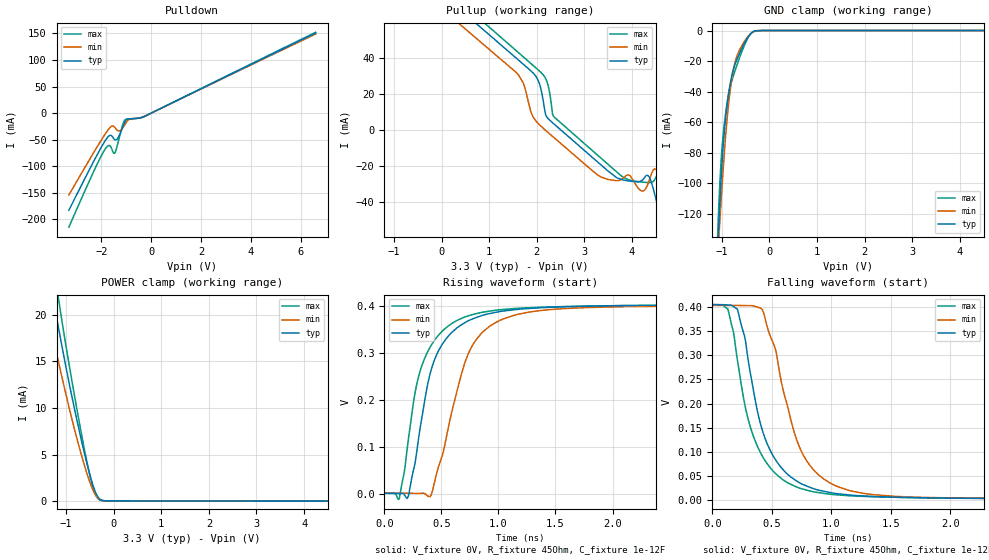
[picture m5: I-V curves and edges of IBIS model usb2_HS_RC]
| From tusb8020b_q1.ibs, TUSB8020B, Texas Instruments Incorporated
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|   USB 2.0 High Speed mode, for DP pin 240MHz (Internal Termination ON) with
|   recommended C load of 1pF.
[Model]   usb2_HS_RC
Model_type   I/O
Polarity   Non-Inverting
Enable   Active-High
Vmeas = 202mV
Vref = 0
Rref = 45
Cref =1pF
Vinl = 150mV
Vinh = 360mV
|   typ   min   max
|EXCEPTION   (nom PVT)   (Slow PVT) (Fast PVT)
C_comp   5.8941pF   5.4228pF   6.1646pF
[Voltage Range]   3.3   2.97   3.465
[Temperature Range]   27   105   -40
[Pullup Reference]   3.3   2.97   3.465
[Pulldown Reference]   0   0   0
[Power Clamp Reference]   3.3   2.97   3.465
[GND Clamp Reference]   0   0   0
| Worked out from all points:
|   slope of the pulldown table from 0 to 0.495 V, typ, clamps not added: 43.6 ohm
|   slope of the pullup table from 0 to 0.495 V, typ, clamps not added: 43.8 ohm
|   GND clamp passes 1 mA (typ) near -0.35 V on its own axis
|   POWER clamp passes 1 mA (typ) near -0.38 V on its own axis
|   falling waveform, V_fixture 0V, R_fixture 45Ohm, C_fixture 1e-12F: 20-80 % time 252ps typ, 275ps min, 250ps max; typ from 0.405 V to 0.002 V
|   rising waveform, V_fixture 0V, R_fixture 45Ohm, C_fixture 1e-12F: 20-80 % time 240ps typ, 278ps min, 235ps max; typ from 0.002 V to 0.404 V
[Pulldown]
|   Voltage   I(typ)   I(min)   I(max)
-3.3V     -182.7mA   -154mA     -214.5mA
-2.109V   -73.47mA   -59.12mA   -90.55mA
-1.836V   -51.34mA   -38.81mA   -67.06mA
-1.687V   -42.74mA   -29.04mA   -60.76mA
-1.588V   -42.26mA   -24.56mA   -66.11mA
-1.464V   -49.94mA   -26.46mA   -75.27mA
-1.265V   -40.67mA   -33.14mA   -44.1mA
-1.141V   -26.63mA   -28.06mA   -22.45mA
-1.042V   -16mA      -21.02mA   -12.18mA
-868.4mV  -10.68mA   -11.28mA   -10.85mA
-297.7mV  -6.74mA    -6.624mA   -6.826mA
6.6V      150.7mA    148.8mA    152.1mA
[GND Clamp]
|   Voltage   I(typ)   I(min)   I(max)
-3.3V     -3.521A    -2.996A    -4.111A
-1.092V   -145.9mA   -151.2mA   -136.4mA
-1.067V   -128.4mA   -137.7mA   -116.4mA
-1.042V   -112.2mA   -124.7mA   -99.36mA
-1.017V   -97.56mA   -112.1mA   -85.68mA
-967.7mV  -73.5mA    -88.57mA   -66.63mA
-893.2mV  -49.51mA   -59.02mA   -47.86mA
-818.8mV  -33.69mA   -37.74mA   -35.76mA
-669.9mV  -17.99mA   -15.57mA   -21.42mA
-471.4mV  -5.326mA   -4.698mA   -5.944mA
-322.6mV  -523.8uA   -615.4uA   -432uA
6.6V      0A         0A         0A
[Pullup]
|   Voltage   I(typ)   I(min)   I(max)
-3.3V     150.7mA    141.5mA    155.9mA
1.563V    39.81mA    31.86mA    43.93mA
1.96V     30.34mA    5.602mA    34.77mA
2.208V    7.102mA    -875.8uA   27.06mA
2.357V    3.277mA    -4.287mA   7.257mA
3.275V    -17.82mA   -24.99mA   -14.06mA
4.342V    -25.52mA   -29.54mA   -29.28mA
4.565V    -44.49mA   -24.78mA   -25.96mA
4.764V    -50.65mA   -42.33mA   -56.23mA
4.913V    -44.86mA   -57.23mA   -80.87mA
5.086V    -57mA      -75.14mA   -71.32mA
6.6V      -238.4mA   -237.7mA   -255.4mA
[POWER Clamp]
|   Voltage   I(typ)   I(min)   I(max)
-3.3V     96.76mA    79.79mA    115.2mA
-1.538V   29.26mA    23.71mA    34.64mA
-1.365V   24.34mA    19.65mA    28.67mA
-1.315V   22.95mA    18.5mA     26.98mA
-1.216V   20.19mA    16.23mA    23.63mA
-1.141V   18.14mA    14.55mA    21.16mA
-843.6mV  10.42mA    8.146mA    11.95mA
-570.7mV  4.224mA    3.128mA    4.449mA
-421.8mV  1.503mA    1.054mA    1.277mA
-372.2mV  844uA      587uA      607.5uA
-297.7mV  244.6uA    181.6uA    136.8uA
6.6V      0A         0A         0A
[Ramp]
R_load = 45
|   typ   min   max
dV/dt_r   0.241364/2.40298e-10   0.240102/2.77902e-10   0.241582/2.34784e-10
dV/dt_f   0.24137/2.52037e-10   0.240087/2.75243e-10   0.241515/2.50484e-10
[Falling Waveform]
V_fixture = 0V
V_fixture_min = 0V
V_fixture_max = 0V
R_fixture = 45Ohm
C_fixture = 1e-12F
|   Time   V(typ)   V(min)   V(max)
0s        404.5mV    402.7mV    404.6mV
130ps     403.7mV    402.8mV    395.2mV
210ps     394.8mV    402.7mV    290.8mV
300ps     291.2mV    402.3mV    168.3mV
420ps     144.6mV    393.5mV    91.43mV
530ps     84.09mV    312.2mV    55.57mV
680ps     44.73mV    147.1mV    30.66mV
860ps     23.36mV    60.43mV    17.27mV
1.18ns    10.47mV    18.61mV    9.102mV
3.5ns     2.259mV    2.567mV    2.121mV
[Rising Waveform]
V_fixture = 0V
V_fixture_min = 0V
V_fixture_max = 0V
R_fixture = 45Ohm
C_fixture = 1e-12F
|   Time   V(typ)   V(min)   V(max)
0s        1.753mV    1.976mV    1.462mV
130ps     1.073mV    1.846mV    -10.27mV
210ps     -4.468mV   1.677mV    116.9mV
290ps     102.3mV    1.34mV     241.2mV
400ps     256.1mV    -5.588mV   312.8mV
500ps     316.5mV    76.65mV    345.6mV
640ps     355mV      223.1mV    370.5mV
810ps     376.8mV    331mV      384.9mV
1.14ns    393mV      381.4mV    395.5mV
3.5ns     404mV      402.1mV    404.1mV
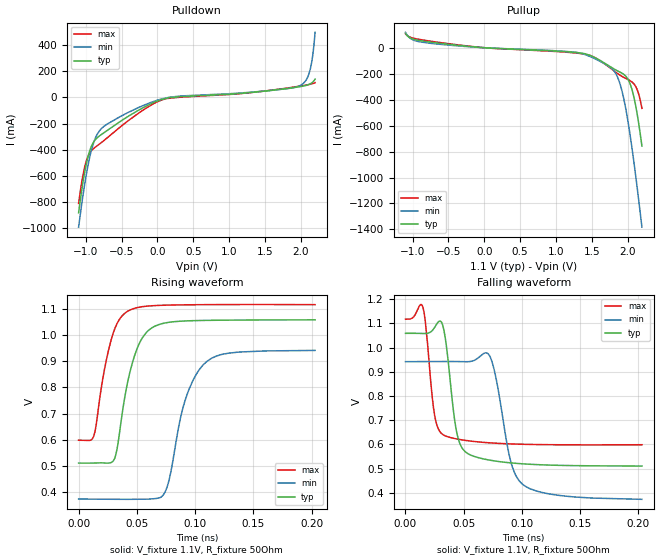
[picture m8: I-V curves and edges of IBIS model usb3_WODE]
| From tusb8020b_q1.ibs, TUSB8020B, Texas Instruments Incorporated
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|   USB 3.0 No De-Emphasis mode, for SSTXP/N pin  2.5GHz
[Model]   usb3_WODE
Model_type   Output
Polarity   Non-Inverting
Vmeas = 0.75
Vref = 1.1
Rref = 50
|   typ   min   max
|   (nom PVT)   (Fast PVT)   (slow PVT)
C_comp   0.5286pF   0.5195pF   0.5464pF
[Voltage Range]   1.1   0.99   1.155
[Temperature Range]   27   105   -40
[Pullup Reference]   1.1   0.99   1.155
[Pulldown Reference]   0   0   0
[Power Clamp Reference]   1.1   0.99   1.155
[GND Clamp Reference]   0   0   0
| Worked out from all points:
|   slope of the pulldown table from 0 to 0.165 V, typ, clamps not added: 6.7 ohm
|   slope of the pullup table from 0 to 0.165 V, typ, clamps not added: 31.1 ohm
|   falling waveform, V_fixture 1.1V, R_fixture 50Ohm: 20-80 % time 8.99ps typ, 13.8ps min, 6.77ps max; typ from 1.06 V to 0.51 V
|   rising waveform, V_fixture 1.1V, R_fixture 50Ohm: 20-80 % time 15.3ps typ, 18.7ps min, 13.6ps max; typ from 0.51 V to 1.06 V
[Pulldown]
|   Voltage   I(typ)   I(min)   I(max)
-1.1V     -882.4mA   -992.9mA   -811.1mA
-1.017V   -579.6mA   -673.2mA   -537.6mA
-942.9mV  -405.4mA   -453.1mA   -424mA
-851.9mV  -314.6mA   -294.1mA   -374.2mA
-752.6mV  -272.7mA   -224.2mA   -332.7mA
-272.9mV  -100.7mA   -79.78mA   -124.3mA
74.44mV   -13.02mA   -9.468mA   -16.58mA
1.985V    82.05mA    89.01mA    86.68mA
2.068V    90.95mA    126.5mA    93.9mA
2.126V    102mA      201mA      100.1mA
2.167V    117.1mA    320mA      106.1mA
2.2V      139.9mA    498.5mA    113mA
[Pullup]
|   Voltage   I(typ)   I(min)   I(max)
-1.1V     113.7mA    121.3mA    110.2mA
-992.5mV  68.76mA    62.34mA    76.36mA
-760.9mV  45.98mA    37.07mA    53.88mA
24.81mV   1.446mA    1.636mA    1.318mA
1.406V    -44.63mA   -50.53mA   -47.08mA
1.77V     -147.9mA   -154mA     -159.6mA
1.877V    -181.7mA   -249.3mA   -203.5mA
1.968V    -213.9mA   -450.7mA   -232.4mA
2.026V    -265.2mA   -640.2mA   -249.1mA
2.084V    -370mA     -865.4mA   -274.6mA
2.142V    -537.7mA   -1.116A    -333.8mA
2.2V      -757mA     -1.383A    -465.6mA
[Ramp]
R_load = 50
|   typ   min   max
dV/dt_r   0.328876/1.53144e-11   0.341033/1.87105e-11   0.311149/1.36392e-11
dV/dt_f   0.328891/8.99406e-12   0.341098/1.37718e-11   0.311003/6.76744e-12
[Falling Waveform]
V_fixture = 1.1V
V_fixture_min = 0.99V
V_fixture_max = 1.155V
R_fixture = 50Ohm
C_fixture = 0F
|   Time   V(typ)   V(min)   V(max)
0s        1.059V     941.6mV    1.117V
15ps      1.058V     941.9mV    1.167V
25ps      1.083V     942.1mV    720.9mV
33ps      1.072V     942.2mV    638mV
44ps      649.6mV    942mV      622.4mV
53ps      563.5mV    941.4mV    615.4mV
73ps      534.3mV    958mV      606.2mV
90ps      523.8mV    536.5mV    602mV
101ps     519.6mV    433.3mV    600.4mV
203ps     510.4mV    373.1mV    598.5mV
[Rising Waveform]
V_fixture = 1.1V
V_fixture_min = 0.99V
V_fixture_max = 1.155V
R_fixture = 50Ohm
C_fixture = 0F
|   Time   V(typ)   V(min)   V(max)
0s        510.5mV    373.3mV    598.1mV
13ps      510.7mV    372.6mV    613.6mV
22ps      510.9mV    372.3mV    863.8mV
30ps      520.3mV    372mV      1.012V
42ps      817.9mV    371.8mV    1.091V
55ps      991.7mV    372.3mV    1.109V
74ps      1.046V     398.1mV    1.115V
92ps      1.054V     758.2mV    1.116V
110ps     1.057V     898.9mV    1.117V
203ps     1.059V     941.6mV    1.117V
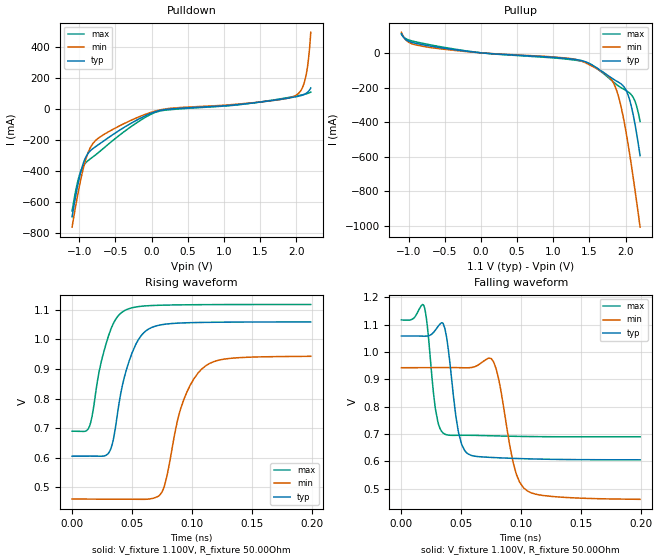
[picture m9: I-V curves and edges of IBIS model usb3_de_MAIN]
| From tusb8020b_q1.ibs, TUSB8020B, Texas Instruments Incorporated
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|USB 3.0 De-Emphasis MAIN Buffer, for SSTXP/SSTXN pins 2.5GHz(1.25GHz to see De-Emphasis)
[Model]   usb3_de_MAIN
Model_type   Output
Vmeas = 0.8
Vref = 1.1
Rref = 50
C_comp   0.5286pF   0.5195pF   0.5464pF
[Voltage Range]   1.1   0.99   1.155
[Temperature Range]   27   105   -40
[Pullup Reference]   1.1   0.99   1.155
[Pulldown Reference]   -0   -0   -0
[Power Clamp Reference]   1.1   0.99   1.155
[GND Clamp Reference]   -0   -0   -0
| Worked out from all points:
|   slope of the pulldown table from 0 to 0.165 V, typ, clamps not added: 7.83 ohm
|   slope of the pullup table from 0 to 0.165 V, typ, clamps not added: 30.4 ohm
|   falling waveform, V_fixture 1.100V, R_fixture 50.00Ohm: 20-80 % time 7.94ps typ, 12.1ps min, 6.06ps max; typ from 1.06 V to 0.605 V
|   rising waveform, V_fixture 1.100V, R_fixture 50.00Ohm: 20-80 % time 15.6ps typ, 18.7ps min, 14.1ps max; typ from 0.605 V to 1.06 V
[Pulldown]
|   Voltage   I(typ)   I(min)   I(max)
-1.1V     -696.3mA   -762.7mA   -658.5mA
-1.017V   -482.8mA   -542.2mA   -459.3mA
-942.9mV  -348.4mA   -380.8mA   -366.2mA
-860.2mV  -276.3mA   -262mA     -326.5mA
-760.9mV  -239mA     -197.7mA   -291.2mA
-256.4mV  -85.42mA   -67.68mA   -105.3mA
99.25mV   -11.89mA   -8.313mA   -15.58mA
1.977V    76.75mA    82.46mA    81.25mA
2.059V    85.22mA    115.8mA    88.44mA
2.117V    95.32mA    181mA      94.39mA
2.167V    112.5mA    315.4mA    101.4mA
2.2V      135.3mA    493.8mA    108.3mA
[Pullup]
|   Voltage   I(typ)   I(min)   I(max)
-1.1V     113.7mA    121.3mA    110.2mA
-1.001V   70.28mA    64.42mA    77.6mA
-769.2mV  46.62mA    37.62mA    54.61mA
0V        2.426mA    2.416mA    2.485mA
1.398V    -42.93mA   -46.86mA   -46.14mA
1.753V    -128.1mA   -131.2mA   -138.3mA
1.861V    -157.9mA   -198.3mA   -176.3mA
1.96V     -186mA     -354.6mA   -204.7mA
2.026V    -233.3mA   -507.1mA   -221.1mA
2.076V    -302.3mA   -638.6mA   -239mA
2.142V    -440.6mA   -829.4mA   -293mA
2.2V      -593.4mA   -1.007A    -395.5mA
[Ramp]
R_load = 50.00Ohm
|   typ   min   max
dV/dt_r   271.949mV/15.625ps  289.075mV/18.671ps  256.692mV/14.067ps
dV/dt_f   271.945mV/7.956ps   289.075mV/12.138ps  256.673mV/6.060ps
[Falling Waveform]
V_fixture = 1.100V
V_fixture_min = 990.000mV
V_fixture_max = 1.155V
R_fixture = 50.00Ohm
|   Time   V(typ)   V(min)   V(max)
0s        1.059V     942.5mV    1.117V
18.63ps   1.058V     942.8mV    1.171V
28.48ps   1.081V     943mV      789.9mV
36.18ps   1.088V     943.1mV    699.5mV
47.67ps   705.5mV    942.9mV    695.2mV
55.58ps   627.3mV    942.3mV    695.3mV
77.14ps   613.7mV    962.7mV    693.2mV
93.35ps   610.7mV    594.9mV    691.6mV
105.3ps   609.1mV    491.1mV    690.8mV
199.4ps   605.5mV    460.7mV    689.6mV
[Rising Waveform]
V_fixture = 1.100V
V_fixture_min = 990.000mV
V_fixture_max = 1.155V
R_fixture = 50.00Ohm
|   Time   V(typ)   V(min)   V(max)
0s        605.4mV    460.7mV    689.7mV
14.55ps   605.4mV    460.3mV    706.2mV
22.72ps   605.2mV    460.1mV    893.4mV
31.07ps   619.1mV    460mV      1.019V
43.89ps   875.7mV    459.9mV    1.097V
58.21ps   1.015V     459.5mV    1.112V
75.08ps   1.049V     483.8mV    1.115V
93.35ps   1.055V     797mV      1.116V
112ps     1.057V     911.5mV    1.117V
199.4ps   1.059V     942.5mV    1.117V
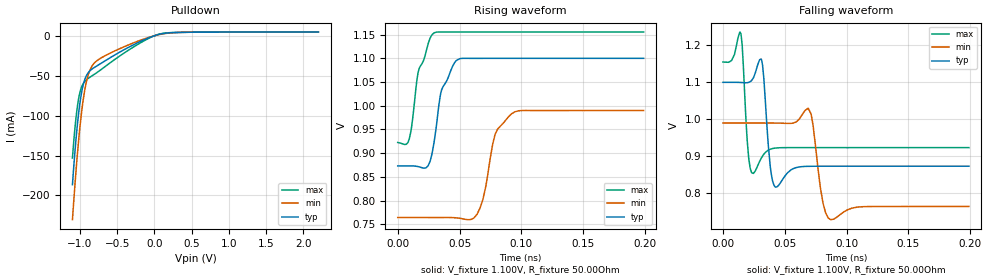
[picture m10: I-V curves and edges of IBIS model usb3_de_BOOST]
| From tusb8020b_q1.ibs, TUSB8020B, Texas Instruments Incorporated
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|USB 3.0 De-Emphasis BOOST Buffer, for SSTXP/SSTXN pins 2.5GHz(1.25GHz to see De-Emphasis)
[Model]   usb3_de_BOOST
Model_type   Open_drain
Vmeas = 1.1
Vref = 1.1
Rref = 50
|   typ   min   max
C_comp   0 0 0
[Voltage Range]   1.1   0.99   1.155
[Temperature Range]   27   105   -40
[Pullup Reference]   1.1   0.99   1.155
[Pulldown Reference]   -0   -0   -0
[Power Clamp Reference]   1.1   0.99   1.155
[GND Clamp Reference]   -0   -0   -0
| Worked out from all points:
|   slope of the pulldown table from 0 to 0.165 V, typ, clamps not added: 49.2 ohm
|   falling waveform, V_fixture 1.100V, R_fixture 50.00Ohm: 20-80 % time 2.8ps typ, 4.83ps min, 2.11ps max; typ from 1.1 V to 0.873 V
|   rising waveform, V_fixture 1.100V, R_fixture 50.00Ohm: 20-80 % time 10.9ps typ, 10.2ps min, 10.5ps max; typ from 0.873 V to 1.1 V
[Pulldown]
|   Voltage   I(typ)   I(min)   I(max)
-1.1V     -186.5mA   -230.4mA   -153.2mA
-1.059V   -136.5mA   -177.1mA   -108.3mA
-1.026V   -104.1mA   -139.8mA   -83.47mA
-992.5mV  -79.66mA   -108.1mA   -68.49mA
-951.1mV  -60.01mA   -77.44mA   -59.34mA
-918mV    -51.1mA    -60.02mA   -55.69mA
-876.7mV  -44.99mA   -45.82mA   -52.63mA
-827.1mV  -40.98mA   -36.55mA   -49.55mA
-769.2mV  -37.6mA    -31.08mA   -45.96mA
-231.6mV  -9.073mA   -7.158mA   -11.32mA
107.5mV   2.587mA    2.218mA    2.914mA
2.2V      4.622mA    4.623mA    4.729mA
[Ramp]
R_load = 50.00Ohm
|   typ   min   max
dV/dt_r   136.027mV/10.900ps  135.281mV/10.178ps  139.729mV/10.533ps
dV/dt_f   136.008mV/2.805ps   135.281mV/4.827ps   138.873mV/2.140ps
[Falling Waveform]
V_fixture = 1.100V
V_fixture_min = 990.000mV
V_fixture_max = 1.155V
R_fixture = 50.00Ohm
|   Time   V(typ)   V(min)   V(max)
0s        1.1V       990mV      1.155V
14.54ps   1.1V       990mV      1.231V
19.62ps   1.099V     990mV      941.1mV
23.19ps   1.105V     990mV      855.4mV
31.28ps   1.16V      990mV      896.9mV
38.14ps   875.1mV    990mV      919.1mV
42.67ps   816.8mV    989.9mV    922.5mV
68.98ps   873mV      1.03V      923.6mV
87.19ps   873.3mV    728.8mV    923.5mV
198.9ps   873.3mV    764.5mV    923.5mV
[Rising Waveform]
V_fixture = 1.100V
V_fixture_min = 990.000mV
V_fixture_max = 1.155V
R_fixture = 50.00Ohm
|   Time   V(typ)   V(min)   V(max)
0s        873.3mV    764.5mV    922.7mV
9.282ps   873.3mV    764.5mV    929.5mV
16.48ps   871.8mV    764.5mV    1.07V
29.69ps   928.2mV    764.5mV    1.154V
35.48ps   1.033V     764.5mV    1.155V
50.14ps   1.099V     762.9mV    1.156V
64.18ps   1.1V       771.6mV    1.156V
78.86ps   1.1V       940.7mV    1.156V
92.25ps   1.1V       983.5mV    1.156V
198.9ps   1.1V       990mV      1.156V
